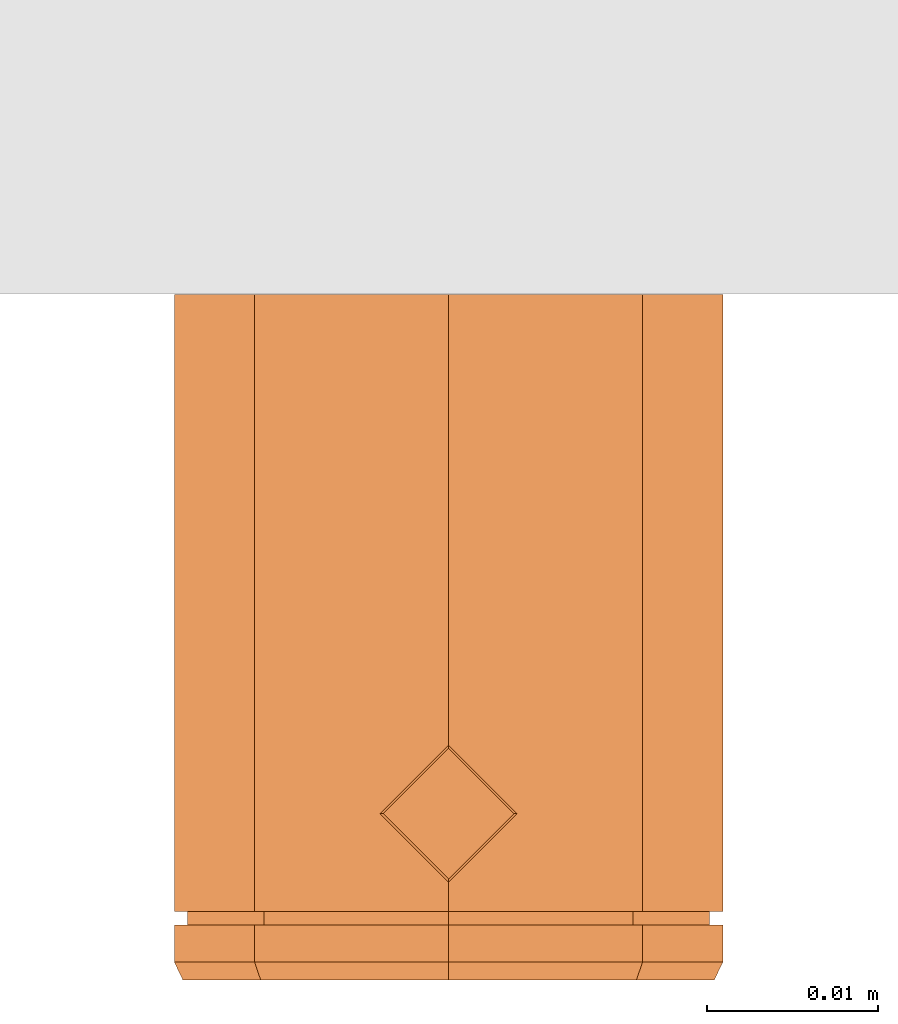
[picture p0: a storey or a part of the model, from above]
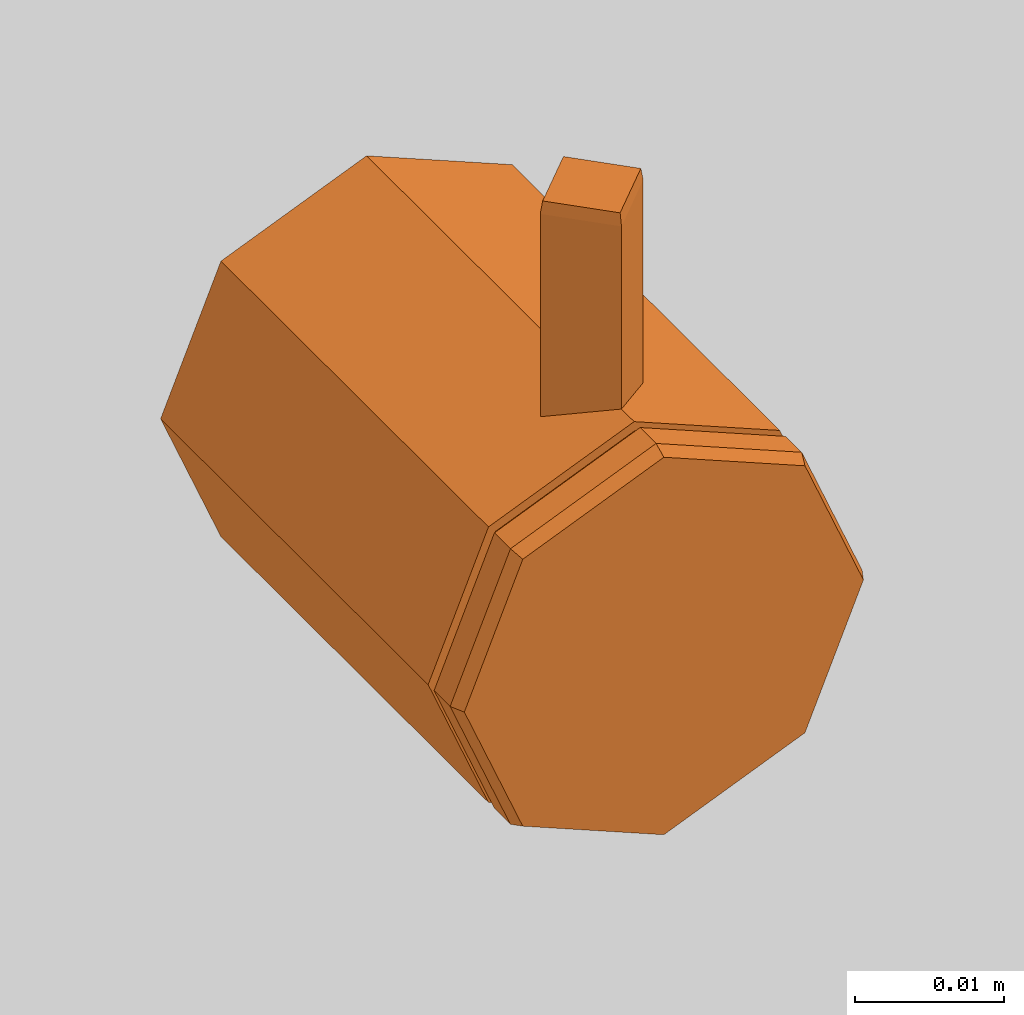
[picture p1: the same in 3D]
Properties of the parts of a building model (IFC2X3)

# File
Description: ViewDefinition [CoordinationView]
Time: 2018-02-06T14:46:56
Written by: The EXPRESS Data Manager Version 5.01.0100.02.64mod : 6 Jun 2012
Made in: 20140709_2115(x64) - Exporter 2014.0.2014.0709 - Default UI
Comment: STEP Physical File produced by: The EXPRESS Data Manager Version 5.01.0100.02.64mod : 6 Jun 2012 * Module: EDMstepFileFactory/EDMstandAlone * Creation date: Tue Feb 06 14:46:56 2018 * Host: BIM-HP * Database: C:\Users\dcole\AppData\Local\Temp\{0B1FF4F6-DBB6-45E4-99C4-28989198DB32}\ifc * Database version: 5507 * Database creation date: Tue Feb 06 14:46:54 2018 * Schema: IFC2X3 * Model: DataRepository.ifc * Model creation date: Tue Feb 06 14:46:55 2018 * Header model: DataRepository.ifc_HeaderModel * Header model creation date: Tue Feb 06 14:46:55 2018 * EDMuser: sdai-user * EDMgroup: sdai-group * License ID and type: 5605 : Permanent license. Expiry date: * EDMstepFileFactory options: 020000

# IfcProject
LongName: P:\Fastrack\53721_DOLPHIN SOLUTIONS LIMITED\ADDITIONAL DRAWINGS 2018 BIM\IFC\13-1657.ifc

# IfcSite, Default
RefLatitude: 42, 24, 53, 508911; RefLongitude: -71, -15, -29, -58837; RefElevation: 0 mm

# IfcBuilding
Pset_BuildingCommon - NumberOfStoreys: 1

# IfcBuildingStorey, Level 1
LongName: Level 1; Elevation: 0 mm
Constraints - Elevation Base: Project Base Point; Elevation: 0 mm
Dimensions - Computation Height: 0 mm
Identity Data - Structural: no; Name: Level 1; Building Story: yes
Graphics - Line Pattern: -3000010; Symbol at End 1 Default: no; Line Weight: 1; Color: 0; Symbol at End 2 Default: yes

# IfcBuildingElementProxy: 13.1657 Dolphin Large Robe Hook - with Pin, 13-1657:13.1657 Dolphin Large Robe Hook - with Pin:76548
In: Level 1
Constraints - Offset: 490.532 mm; Moves With Nearby Elements: no; Host: Level : Level 1; Level: Level: Level 1
Phasing - Phase Created: New Construction
Dimensions - Volume: 0.0000334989 m3; Width: Ø32mm; Height: 48mm; Projection: 40mm
Pset_ManufacturerTypeInformation - Manufacturer: Dolphin Solutions Ltd.
Pset_BuildingElementProxyCommon - Reference: 13.1657 Dolphin Large Robe Hook - with Pin
Identity Data - Assembly Description: Other Plumbing Fixtures; URL: www.dolphinsolutions.co.uk; Fax No.: +44 (0) 1424 205 200; Address: Southpoint, Compass Park, Bodiam, Robertsbridge, TN32 5BS; Tel No.: +44 (0) 1424 202 224; Model: 13.1657; Assembly Code: D2010900; Description: Large robe hook with pin; Email: info@dolphinsolutions.co.uk; Manufacturer: Dolphin Solutions Ltd.
General - Care and Maintenance: Clean with soap and warm water, dry with a cleansoft cloth. To maintain finish use any industrial steel cleaner; polishing along the material grain with a clean soft cloth. Abrasive cleaners, chloride cleaning agents and carbon steel brushes/steel wool will scratch the stainless steel and should not be used.; Warranty: 12 months from date of purchase.; Product Data: Large brushed finish stainless steel robe hook with pin.; Product Page Link: https://www.dolphinsolutions.co.uk/product/dolphin-large-robe-hook-pin
Materials and Finishes - Material: Satin finish stainless steel grade 1.4301 (304)

# IfcWallStandardCase: Basic Wall:Wall 1, Basic Wall:Wall 1:3092
In: Level 1
Type - PredefinedType: STANDARD; Material: Default Wall 50 mm
Type - Construction - Wrapping at Inserts: Do not wrap; Width: 50 mm; Function: Exterior
Type - Graphics - Coarse Scale Fill Color: 8454143
Type - Analytical Properties - Roughness: 1; Absorptance: 0.1
Constraints - Unconnected Height: 936.967 mm; Top Extension Distance: 0 mm; Top Offset: 0 mm; Related to Mass: no; Room Bounding: yes; Base Extension Distance: 0 mm; Location Line: Finish Face: Interior; Base is Attached: no; Top is Attached: no; Base Constraint: Level: Level 1; Base Offset: 0 mm
Structural - Structural Usage: Non-bearing; Enable Analytical Model: no; Structural: no
Phasing - Phase Created: New Construction
Dimensions - Length: 640 mm; Area: 0.599659 m2; Volume: 0.0299829 m3
Pset_WallCommon - Reference: Wall 1; LoadBearing: no; ExtendToStructure: no; IsExternal: yes
